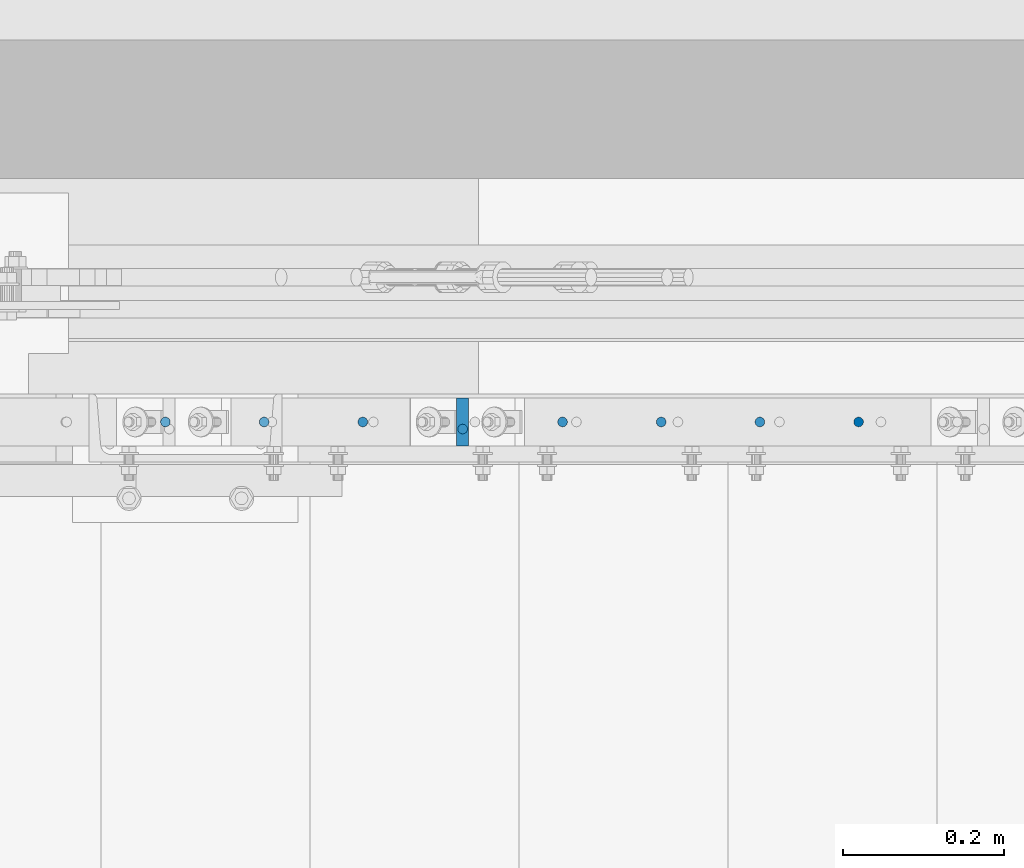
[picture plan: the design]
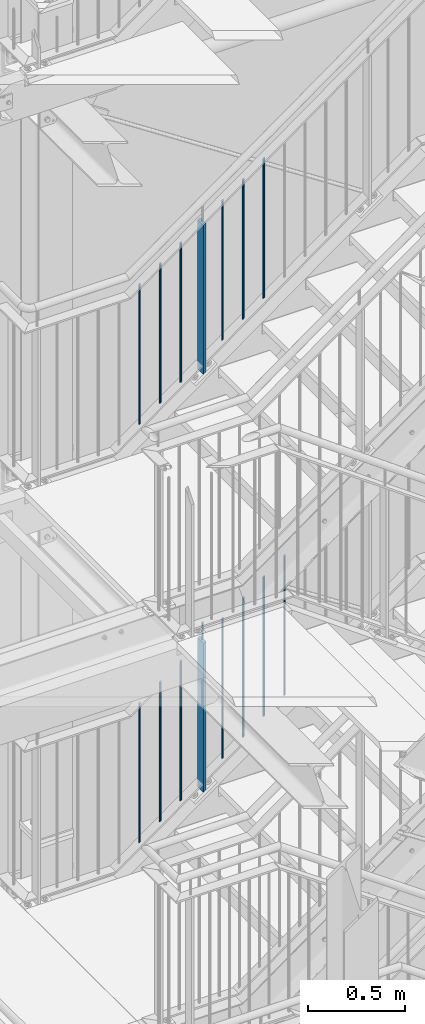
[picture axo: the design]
# One storey, part 75 of 825: 16 columns.
"""IFC2X3 building model written with IfcOpenShell, lengths in millimetres."""

from ifc_helpers import new_model, entity, si_unit, converted_unit, frame, origin, origin_with_axes, origin_2d, place, context, project, spatial, rectangle, circle, extrude, clip, halfspace, material, element, save


model = new_model("IFC2X3")

# Units and contexts
model_context = context("Model", 3, precision=1e-09, world=origin_with_axes())
ifc_project = project(units=[si_unit("LENGTHUNIT", "METRE", prefix="MILLI"), si_unit("AREAUNIT", "SQUARE_METRE"), si_unit("VOLUMEUNIT", "CUBIC_METRE"), converted_unit("PLANEANGLEUNIT", "DEGREE", entity("IfcPlaneAngleMeasure", 0.01745329), si_unit("PLANEANGLEUNIT", "RADIAN"), dimensions=[0, 0, 0, 0, 0, 0, 0])], contexts=[model_context])

# Site, building, storey
site_placement = place(None, origin_with_axes())
site = spatial("IfcSite", under=ifc_project, at=site_placement, CompositionType="ELEMENT")
building_placement = place(site_placement, origin_with_axes())
building = spatial("IfcBuilding", under=site, at=building_placement, Name="1", CompositionType="ELEMENT")
storey_placement = place(building_placement, origin_with_axes())
storey = spatial("IfcBuildingStorey", under=building, at=storey_placement, Name="Default Storey", CompositionType="ELEMENT", Elevation=0.0)

# Columns
ifc_material = material(Name="S235JR")
column_1_placement = place(None, frame((5686.71354585, 7356.736971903, 8685.043251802), z_axis=(0.0, 0.0, 1.0), x_axis=(1.0, 0.0, 0.0)))
element("IfcColumn", 1, at=column_1_placement, inside=storey, material=ifc_material, Name="Railing_Post_Stair#1", ObjectType="Railing_Post_Stair#1", context=model_context, shape_type="Clipping", body=[
    clip(clip(extrude(rectangle(XDim=15.0, YDim=60.0, at=origin_2d()), origin(), (0.0, 0.0, -1.0), 1013.13824851), halfspace(frame((-7395.184691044, -7356.736971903, -6322.264008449), z_axis=(-0.585945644, 0.0, 0.810350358), x_axis=(0.0, -1.0, 0.0)), True)), halfspace(frame((-7840.004364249, -7356.736971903, -5707.087864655), z_axis=(0.585945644, 0.0, -0.810350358), x_axis=(0.0, 1.0, 0.0)), True)),
])
column_2_placement = place(None, frame((5316.963498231, 7356.736971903, 8389.996253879), z_axis=(0.0, 0.0, 1.0), x_axis=(1.0, 0.0, 0.0)))
element("IfcColumn", 2, at=column_2_placement, inside=storey, material=ifc_material, Name="Railing_Picket_Stair#4", ObjectType="Railing_Picket_Stair#4", context=model_context, shape_type="Clipping", body=[
    clip(clip(extrude(circle(Radius=6.0, at=origin_2d()), origin(), (0.0, 0.0, -1.0), 896.057999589), halfspace(frame((-7470.25431663, -7356.736971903, -5412.040866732), z_axis=(0.585945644, 0.0, -0.810350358), x_axis=(0.0, 1.0, 0.0)), True)), halfspace(frame((-7054.731925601, -7356.736971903, -5986.699492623), z_axis=(-0.585945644, 0.0, 0.810350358), x_axis=(0.0, -1.0, 0.0)), True)),
])
column_3_placement = place(None, frame((5439.713522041, 7356.736971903, 8478.753963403), z_axis=(0.0, 0.0, 1.0), x_axis=(1.0, 0.0, 0.0)))
element("IfcColumn", 3, at=column_3_placement, inside=storey, material=ifc_material, Name="Railing_Picket_Stair#5", ObjectType="Railing_Picket_Stair#5", context=model_context, shape_type="Clipping", body=[
    clip(clip(extrude(circle(Radius=6.0, at=origin_2d()), origin(), (0.0, 0.0, -1.0), 896.057999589), halfspace(frame((-7593.004340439, -7356.736971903, -5500.798576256), z_axis=(0.585945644, 0.0, -0.810350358), x_axis=(0.0, 1.0, 0.0)), True)), halfspace(frame((-7177.48194941, -7356.736971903, -6075.457202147), z_axis=(-0.585945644, 0.0, 0.810350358), x_axis=(0.0, -1.0, 0.0)), True)),
])
column_4_placement = place(None, frame((5562.46354585, 7356.736971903, 8567.511672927), z_axis=(0.0, 0.0, 1.0), x_axis=(1.0, 0.0, 0.0)))
element("IfcColumn", 4, at=column_4_placement, inside=storey, material=ifc_material, Name="Railing_Picket_Stair#6", ObjectType="Railing_Picket_Stair#6", context=model_context, shape_type="Clipping", body=[
    clip(clip(extrude(circle(Radius=6.0, at=origin_2d()), origin(), (0.0, 0.0, -1.0), 896.057999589), halfspace(frame((-7715.754364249, -7356.736971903, -5589.55628578), z_axis=(0.585945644, 0.0, -0.810350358), x_axis=(0.0, 1.0, 0.0)), True)), halfspace(frame((-7300.23197322, -7356.736971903, -6164.214911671), z_axis=(-0.585945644, 0.0, 0.810350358), x_axis=(0.0, -1.0, 0.0)), True)),
])
column_5_placement = place(None, frame((5810.96354585, 7356.736971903, 8747.196288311), z_axis=(0.0, 0.0, 1.0), x_axis=(1.0, 0.0, 0.0)))
element("IfcColumn", 5, at=column_5_placement, inside=storey, material=ifc_material, Name="Railing_Picket_Stair#7", ObjectType="Railing_Picket_Stair#7", context=model_context, shape_type="Clipping", body=[
    clip(clip(extrude(circle(Radius=6.0, at=origin_2d()), origin(), (0.0, 0.0, -1.0), 896.057999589), halfspace(frame((-7964.254364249, -7356.736971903, -5769.240901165), z_axis=(0.585945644, 0.0, -0.810350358), x_axis=(0.0, 1.0, 0.0)), True)), halfspace(frame((-7548.73197322, -7356.736971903, -6343.899527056), z_axis=(-0.585945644, 0.0, 0.810350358), x_axis=(0.0, -1.0, 0.0)), True)),
])
column_6_placement = place(None, frame((5933.71356966, 7356.736971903, 8835.953997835), z_axis=(0.0, 0.0, 1.0), x_axis=(1.0, 0.0, 0.0)))
element("IfcColumn", 6, at=column_6_placement, inside=storey, material=ifc_material, Name="Railing_Picket_Stair#8", ObjectType="Railing_Picket_Stair#8", context=model_context, shape_type="Clipping", body=[
    clip(clip(extrude(circle(Radius=6.0, at=origin_2d()), origin(), (0.0, 0.0, -1.0), 896.057999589), halfspace(frame((-8087.004388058, -7356.736971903, -5857.998610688), z_axis=(0.585945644, 0.0, -0.810350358), x_axis=(0.0, 1.0, 0.0)), True)), halfspace(frame((-7671.481997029, -7356.736971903, -6432.657236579), z_axis=(-0.585945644, 0.0, 0.810350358), x_axis=(0.0, -1.0, 0.0)), True)),
])
column_7_placement = place(None, frame((6056.463593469, 7356.736971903, 8924.711707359), z_axis=(0.0, 0.0, 1.0), x_axis=(1.0, 0.0, 0.0)))
element("IfcColumn", 7, at=column_7_placement, inside=storey, material=ifc_material, Name="Railing_Picket_Stair#9", ObjectType="Railing_Picket_Stair#9", context=model_context, shape_type="Clipping", body=[
    clip(clip(extrude(circle(Radius=6.0, at=origin_2d()), origin(), (0.0, 0.0, -1.0), 896.057999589), halfspace(frame((-8209.754411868, -7356.736971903, -5946.756320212), z_axis=(0.585945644, 0.0, -0.810350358), x_axis=(0.0, 1.0, 0.0)), True)), halfspace(frame((-7794.232020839, -7356.736971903, -6521.414946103), z_axis=(-0.585945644, 0.0, 0.810350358), x_axis=(0.0, -1.0, 0.0)), True)),
])
column_8_placement = place(None, frame((6179.213617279, 7356.736971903, 9013.469416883), z_axis=(0.0, 0.0, 1.0), x_axis=(1.0, 0.0, 0.0)))
element("IfcColumn", 8, at=column_8_placement, inside=storey, material=ifc_material, Name="Railing_Picket_Stair#10", ObjectType="Railing_Picket_Stair#10", context=model_context, shape_type="Clipping", body=[
    clip(clip(extrude(circle(Radius=6.0, at=origin_2d()), origin(), (0.0, 0.0, -1.0), 896.057999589), halfspace(frame((-8332.504435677, -7356.736971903, -6035.514029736), z_axis=(0.585945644, 0.0, -0.810350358), x_axis=(0.0, 1.0, 0.0)), True)), halfspace(frame((-7916.982044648, -7356.736971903, -6610.172655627), z_axis=(-0.585945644, 0.0, 0.810350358), x_axis=(0.0, -1.0, 0.0)), True)),
])
column_9_placement = place(None, frame((5686.71354585, 7347.936971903, 8769.69432193), z_axis=(0.0, 0.0, 1.0), x_axis=(0.0, -1.0, 0.0)))
element("IfcColumn", 9, at=column_9_placement, inside=storey, material=ifc_material, Name="Bar#1", ObjectType="Bar#1", context=model_context, shape_type="Clipping", body=[
    clip(clip(extrude(circle(Radius=6.0, at=origin_2d()), origin(), (0.0, 0.0, -1.0), 120.942253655), halfspace(frame((7347.936971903, -7845.864992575, -5783.633810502), z_axis=(0.0, -0.585945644, 0.810350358), x_axis=(1.0, 0.0, 0.0)), True)), halfspace(frame((7347.936971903, -7893.345946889, -5717.968660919), z_axis=(0.0, 0.585945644, -0.810350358), x_axis=(-1.0, 0.0, 0.0)), True)),
])
column_10_placement = place(None, frame((5686.71354585, 7356.736971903, 11316.425342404), z_axis=(0.0, 0.0, 1.0), x_axis=(1.0, 0.0, 0.0)))
element("IfcColumn", 10, at=column_10_placement, inside=storey, material=ifc_material, Name="Railing_Post_Stair#1", ObjectType="Railing_Post_Stair#1", context=model_context, shape_type="Clipping", body=[
    clip(clip(extrude(rectangle(XDim=15.0, YDim=60.0, at=origin_2d()), origin(), (0.0, 0.0, -1.0), 1013.129684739), halfspace(frame((-8646.553290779, -7356.736971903, -7215.238944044), z_axis=(-0.585213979, 0.0, 0.810878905), x_axis=(0.0, -1.0, 0.0)), True)), halfspace(frame((-9091.126835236, -7356.736971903, -6599.232967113), z_axis=(0.585213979, 0.0, -0.810878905), x_axis=(0.0, 1.0, 0.0)), True)),
])
column_11_placement = place(None, frame((5316.963498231, 7356.736971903, 11021.904291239), z_axis=(0.0, 0.0, 1.0), x_axis=(1.0, 0.0, 0.0)))
element("IfcColumn", 11, at=column_11_placement, inside=storey, material=ifc_material, Name="Railing_Picket_Stair#4", ObjectType="Railing_Picket_Stair#4", context=model_context, shape_type="Clipping", body=[
    clip(clip(extrude(circle(Radius=6.0, at=origin_2d()), origin(), (0.0, 0.0, -1.0), 896.125751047), halfspace(frame((-8721.376787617, -7356.736971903, -6304.711915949), z_axis=(0.585213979, 0.0, -0.810878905), x_axis=(0.0, 1.0, 0.0)), True)), halfspace(frame((-8306.06394212, -7356.736971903, -6880.173947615), z_axis=(-0.585213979, 0.0, 0.810878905), x_axis=(0.0, -1.0, 0.0)), True)),
])
column_12_placement = place(None, frame((5439.713522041, 7356.736971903, 11110.493388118), z_axis=(0.0, 0.0, 1.0), x_axis=(1.0, 0.0, 0.0)))
element("IfcColumn", 12, at=column_12_placement, inside=storey, material=ifc_material, Name="Railing_Picket_Stair#5", ObjectType="Railing_Picket_Stair#5", context=model_context, shape_type="Clipping", body=[
    clip(clip(extrude(circle(Radius=6.0, at=origin_2d()), origin(), (0.0, 0.0, -1.0), 896.125751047), halfspace(frame((-8844.126811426, -7356.736971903, -6393.301012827), z_axis=(0.585213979, 0.0, -0.810878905), x_axis=(0.0, 1.0, 0.0)), True)), halfspace(frame((-8428.813965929, -7356.736971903, -6968.763044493), z_axis=(-0.585213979, 0.0, 0.810878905), x_axis=(0.0, -1.0, 0.0)), True)),
])
column_13_placement = place(None, frame((5562.46354585, 7356.736971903, 11199.082484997), z_axis=(0.0, 0.0, 1.0), x_axis=(1.0, 0.0, 0.0)))
element("IfcColumn", 13, at=column_13_placement, inside=storey, material=ifc_material, Name="Railing_Picket_Stair#6", ObjectType="Railing_Picket_Stair#6", context=model_context, shape_type="Clipping", body=[
    clip(clip(extrude(circle(Radius=6.0, at=origin_2d()), origin(), (0.0, 0.0, -1.0), 896.125751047), halfspace(frame((-8966.876835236, -7356.736971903, -6481.890109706), z_axis=(0.585213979, 0.0, -0.810878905), x_axis=(0.0, 1.0, 0.0)), True)), halfspace(frame((-8551.563989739, -7356.736971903, -7057.352141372), z_axis=(-0.585213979, 0.0, 0.810878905), x_axis=(0.0, -1.0, 0.0)), True)),
])
column_14_placement = place(None, frame((5810.96354585, 7356.736971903, 11378.425754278), z_axis=(0.0, 0.0, 1.0), x_axis=(1.0, 0.0, 0.0)))
element("IfcColumn", 14, at=column_14_placement, inside=storey, material=ifc_material, Name="Railing_Picket_Stair#7", ObjectType="Railing_Picket_Stair#7", context=model_context, shape_type="Clipping", body=[
    clip(clip(extrude(circle(Radius=6.0, at=origin_2d()), origin(), (0.0, 0.0, -1.0), 896.125751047), halfspace(frame((-9215.376835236, -7356.736971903, -6661.233378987), z_axis=(0.585213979, 0.0, -0.810878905), x_axis=(0.0, 1.0, 0.0)), True)), halfspace(frame((-8800.063989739, -7356.736971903, -7236.695410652), z_axis=(-0.585213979, 0.0, 0.810878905), x_axis=(0.0, -1.0, 0.0)), True)),
])
column_15_placement = place(None, frame((5933.71356966, 7356.736971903, 11467.014851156), z_axis=(0.0, 0.0, 1.0), x_axis=(1.0, 0.0, 0.0)))
element("IfcColumn", 15, at=column_15_placement, inside=storey, material=ifc_material, Name="Railing_Picket_Stair#8", ObjectType="Railing_Picket_Stair#8", context=model_context, shape_type="Clipping", body=[
    clip(clip(extrude(circle(Radius=6.0, at=origin_2d()), origin(), (0.0, 0.0, -1.0), 896.125751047), halfspace(frame((-9338.126859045, -7356.736971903, -6749.822475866), z_axis=(0.585213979, 0.0, -0.810878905), x_axis=(0.0, 1.0, 0.0)), True)), halfspace(frame((-8922.814013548, -7356.736971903, -7325.284507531), z_axis=(-0.585213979, 0.0, 0.810878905), x_axis=(0.0, -1.0, 0.0)), True)),
])
column_16_placement = place(None, frame((6056.463593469, 7356.736971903, 11555.603948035), z_axis=(0.0, 0.0, 1.0), x_axis=(1.0, 0.0, 0.0)))
element("IfcColumn", 16, at=column_16_placement, inside=storey, material=ifc_material, Name="Railing_Picket_Stair#9", ObjectType="Railing_Picket_Stair#9", context=model_context, shape_type="Clipping", body=[
    clip(clip(extrude(circle(Radius=6.0, at=origin_2d()), origin(), (0.0, 0.0, -1.0), 896.125751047), halfspace(frame((-9460.876882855, -7356.736971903, -6838.411572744), z_axis=(0.585213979, 0.0, -0.810878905), x_axis=(0.0, 1.0, 0.0)), True)), halfspace(frame((-9045.564037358, -7356.736971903, -7413.87360441), z_axis=(-0.585213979, 0.0, 0.810878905), x_axis=(0.0, -1.0, 0.0)), True)),
])

save(model, "model.ifc")
